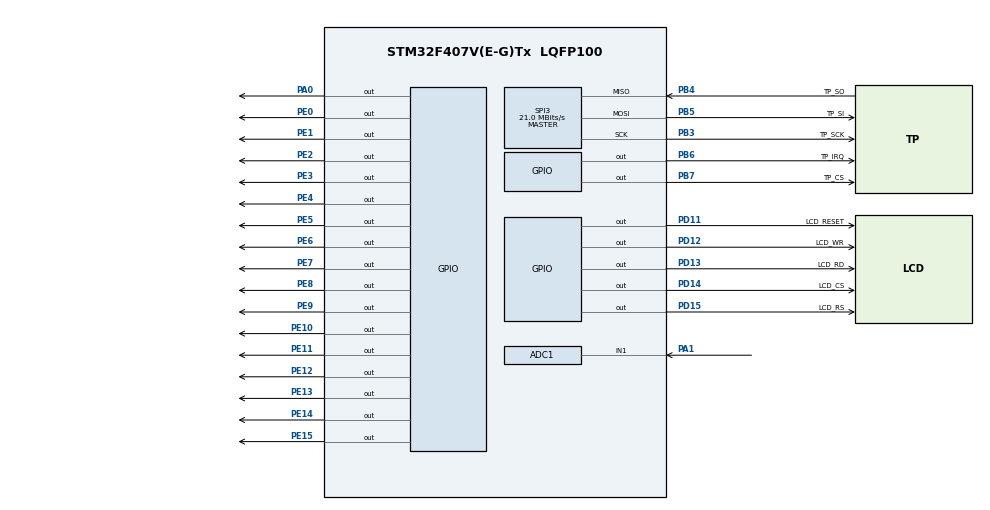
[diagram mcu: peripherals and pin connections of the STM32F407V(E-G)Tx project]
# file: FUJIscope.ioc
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ADC1.Channel-0\#ChannelRegularConversion=ADC_CHANNEL_1
ADC1.ClockPrescaler=ADC_CLOCK_SYNC_PCLK_DIV4
ADC1.ContinuousConvMode=ENABLE
ADC1.DMAContinuousRequests=ENABLE
ADC1.DataAlign=ADC_DATAALIGN_RIGHT
ADC1.DiscontinuousConvMode=DISABLE
ADC1.EOCSelection=ADC_EOC_SINGLE_CONV
ADC1.EnableAnalogWatchDog=false
ADC1.ExternalTrigConv=ADC_SOFTWARE_START
ADC1.ExternalTrigConvEdge=ADC_EXTERNALTRIGCONVEDGE_NONE
ADC1.InjNumberOfConversion=0
ADC1.NbrOfConversion=1
ADC1.NbrOfConversionFlag=1
ADC1.Rank-0\#ChannelRegularConversion=1
ADC1.Resolution=ADC_RESOLUTION_12B
ADC1.SamplingTime-0\#ChannelRegularConversion=ADC_SAMPLETIME_3CYCLES
ADC1.ScanConvMode=ENABLE
ADC1.master=1
Dma.ADC1.0.Direction=DMA_PERIPH_TO_MEMORY
Dma.ADC1.0.FIFOMode=DMA_FIFOMODE_ENABLE
Dma.ADC1.0.FIFOThreshold=DMA_FIFO_THRESHOLD_FULL
Dma.ADC1.0.Instance=DMA2_Stream0
Dma.ADC1.0.MemBurst=DMA_MBURST_SINGLE
Dma.ADC1.0.MemDataAlignment=DMA_MDATAALIGN_HALFWORD
Dma.ADC1.0.MemInc=DMA_MINC_ENABLE
Dma.ADC1.0.Mode=DMA_CIRCULAR
Dma.ADC1.0.PeriphBurst=DMA_PBURST_SINGLE
Dma.ADC1.0.PeriphDataAlignment=DMA_PDATAALIGN_HALFWORD
Dma.ADC1.0.PeriphInc=DMA_PINC_DISABLE
Dma.ADC1.0.Priority=DMA_PRIORITY_LOW
Dma.Request0=ADC1
FREERTOS.Tasks01=defaultTask,0,128,StartDefaultTask,Default,NULL
Mcu.Family=STM32F4
Mcu.Name=STM32F407V(E-G)Tx
Mcu.Package=LQFP100
NVIC.DMA2_Stream0_IRQn=true\:5\:0\:false\:false\:true\:true
NVIC.PriorityGroup=NVIC_PRIORITYGROUP_4
PA0-WKUP.Signal=GPIO_Output
PA1.Signal=ADCx_IN1
PB3.GPIO_Label=TP_SCK
PB3.Mode=Full_Duplex_Master
PB3.Signal=SPI3_SCK
PB4.GPIO_Label=TP_SO
PB4.Mode=Full_Duplex_Master
PB4.Signal=SPI3_MISO
PB5.GPIO_Label=TP_SI
PB5.Mode=Full_Duplex_Master
PB5.Signal=SPI3_MOSI
PB6.GPIO_Label=TP_IRQ
PB6.Signal=GPIO_Output
PB7.GPIO_Label=TP_CS
PB7.Signal=GPIO_Output
PD11.GPIO_Label=LCD_RESET
PD11.Signal=GPIO_Output
PD12.GPIO_Label=LCD_WR
PD12.Signal=GPIO_Output
PD13.GPIO_Label=LCD_RD
PD13.Signal=GPIO_Output
PD14.GPIO_Label=LCD_CS
PD14.Signal=GPIO_Output
PD15.GPIO_Label=LCD_RS
PD15.Signal=GPIO_Output
PE0.Signal=GPIO_Output
PE1.Signal=GPIO_Output
PE10.Signal=GPIO_Output
PE11.Signal=GPIO_Output
PE12.Signal=GPIO_Output
PE13.Signal=GPIO_Output
PE14.Signal=GPIO_Output
PE15.Signal=GPIO_Output
PE2.Signal=GPIO_Output
PE3.Signal=GPIO_Output
PE4.Signal=GPIO_Output
PE5.Signal=GPIO_Output
PE6.Signal=GPIO_Output
PE7.Signal=GPIO_Output
PE8.Signal=GPIO_Output
PE9.Signal=GPIO_Output
PH0-OSC_IN.Mode=HSE-External-Oscillator
PH0-OSC_IN.Signal=RCC_OSC_IN
PH1-OSC_OUT.Mode=HSE-External-Oscillator
PH1-OSC_OUT.Signal=RCC_OSC_OUT
ProjectManager.HeapSize=0x200
ProjectManager.StackSize=0x400
ProjectManager.TargetToolchain=SW4STM32
RCC.48MHZClocksFreq_Value=42000000
RCC.AHBFreq_Value=168000000
RCC.APB1CLKDivider=RCC_HCLK_DIV4
RCC.APB1Freq_Value=42000000
RCC.APB1TimFreq_Value=84000000
RCC.APB2CLKDivider=RCC_HCLK_DIV2
RCC.APB2Freq_Value=84000000
RCC.APB2TimFreq_Value=168000000
RCC.CortexFreq_Value=168000000
RCC.EnbaleCSS=true
RCC.HCLKFreq_Value=168000000
RCC.HSE_VALUE=25000000
RCC.HSI_VALUE=16000000
RCC.LSE_VALUE=32768
RCC.PLLM=25
RCC.PLLN=336
RCC.PLLQ=8
RCC.PLLSourceVirtual=RCC_PLLSOURCE_HSE
RCC.SYSCLKFreq_VALUE=168000000
RCC.SYSCLKSource=RCC_SYSCLKSOURCE_PLLCLK
RCC.VCOOutputFreq_Value=336000000
SH.ADCx_IN1.0=ADC1_IN1,IN1
SPI3.BaudRatePrescaler=SPI_BAUDRATEPRESCALER_2
SPI3.CalculateBaudRate=21.0 MBits/s
SPI3.Direction=SPI_DIRECTION_2LINES
SPI3.Mode=SPI_MODE_MASTER
SPI3.VirtualType=VM_MASTER
VP_FREERTOS_VS_ENABLE.Mode=Enabled
VP_RNG_VS_RNG.Mode=RNG_Activate
board=FUJIscope

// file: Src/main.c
#include <math.h>
#include "main.h"
#include "stm32f4xx_hal.h"
#include "cmsis_os.h"
#include "adc.h"
#include "dma.h"
#include "rng.h"
#include "spi.h"
#include "gpio.h"
#include "LCD.h"
#include "Tpad.h"
#include "ff.h"

#include "gfx.h"
#include "ui.h"

void SystemClock_Config(void);
void Error_Handler(void);
void MX_FREERTOS_Init(void);

#define PI 3.14159265
static uint16_t ADC_buffer[320]={};

osThreadId UI_TaskHandle;
osThreadId ADC_TaskHandle;
__IO uint16_t ADC_val=0;

/*
void LED1_blink_Task(void const * argument)
{
  for(;;)
  {
    HAL_GPIO_TogglePin(GPIOD,GPIO_PIN_12);
    osDelay(500);
  }
}
void LED2_blink_Task(void const * argument)
{
  for(;;)
  {
    HAL_GPIO_TogglePin(GPIOD,GPIO_PIN_13);
    osDelay(1000);
  }
}
*/

void ADC_Task()
{
  MX_ADC1_Init();
  HAL_ADC_Start_DMA(&hadc1, (uint32_t*)&ADC_val,1);
  HAL_ADC_Start(&hadc1);
  while(1)
  {

  }
}

int main(void)
{

  HAL_Init();

  SystemClock_Config();

  MX_GPIO_Init();
  MX_DMA_Init();
  MX_RNG_Init();
  MX_SPI3_Init();
//  LCD_Initializtion();
  MX_ADC1_Init();
  HAL_ADC_Start_DMA(&hadc1, (uint32_t*)&ADC_val,1);
  HAL_ADC_Start(&hadc1);

/*
  osThreadDef(my_ADC_Task, ADC_Task, osPriorityRealtime, 1, 2048);
  ADC_TaskHandle = osThreadCreate(osThread(my_ADC_Task), NULL);
*/
  osThreadDef(UI_Task, UserInterface, osPriorityHigh, 1, 1024);
  UI_TaskHandle = osThreadCreate(osThread(UI_Task), NULL);

  osKernelStart();
}

/** System Clock Configuration
*/
void SystemClock_Config(void)
{

  RCC_OscInitTypeDef RCC_OscInitStruct;
  RCC_ClkInitTypeDef RCC_ClkInitStruct;

    /**Configure the main internal regulator output voltage
    */
  __PWR_CLK_ENABLE();

  __HAL_PWR_VOLTAGESCALING_CONFIG(PWR_REGULATOR_VOLTAGE_SCALE1);

    /**Initializes the CPU, AHB and APB busses clocks
    */
  RCC_OscInitStruct.OscillatorType = RCC_OSCILLATORTYPE_HSE;
  RCC_OscInitStruct.HSEState = RCC_HSE_ON;
  RCC_OscInitStruct.PLL.PLLState = RCC_PLL_ON;
  RCC_OscInitStruct.PLL.PLLSource = RCC_PLLSOURCE_HSE;
  RCC_OscInitStruct.PLL.PLLM = 23;
  RCC_OscInitStruct.PLL.PLLN = 334;
  RCC_OscInitStruct.PLL.PLLP = RCC_PLLP_DIV2;
  RCC_OscInitStruct.PLL.PLLQ = 8;
  HAL_RCC_OscConfig(&RCC_OscInitStruct);

    /**Initializes the CPU, AHB and APB busses clocks
    */
  RCC_ClkInitStruct.ClockType = RCC_CLOCKTYPE_HCLK|RCC_CLOCKTYPE_SYSCLK
                              |RCC_CLOCKTYPE_PCLK1|RCC_CLOCKTYPE_PCLK2;
  RCC_ClkInitStruct.SYSCLKSource = RCC_SYSCLKSOURCE_PLLCLK;
  RCC_ClkInitStruct.AHBCLKDivider = RCC_SYSCLK_DIV1;
  RCC_ClkInitStruct.APB1CLKDivider = RCC_HCLK_DIV4;
  RCC_ClkInitStruct.APB2CLKDivider = RCC_HCLK_DIV2;

  HAL_RCC_ClockConfig(&RCC_ClkInitStruct, FLASH_LATENCY_5);

}

void Error_Handler(void)
{
  while(1)
  {
  }
}

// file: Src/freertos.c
/**
  ******************************************************************************
  * File Name          : freertos.c
  * Description        : Code for freertos applications
  ******************************************************************************
  *
  * Copyright (c) 2017 STMicroelectronics International N.V.
  * All rights reserved.
  *
  * Redistribution and use in source and binary forms, with or without
  * modification, are permitted, provided that the following conditions are met:
  *
  * 1. Redistribution of source code must retain the above copyright notice,
  *    this list of conditions and the following disclaimer.
  * 2. Redistributions in binary form must reproduce the above copyright notice,
  *    this list of conditions and the following disclaimer in the documentation
  *    and/or other materials provided with the distribution.
  * 3. Neither the name of STMicroelectronics nor the names of other
  *    contributors to this software may be used to endorse or promote products
  *    derived from this software without specific written permission.
  * 4. This software, including modifications and/or derivative works of this
  *    software, must execute solely and exclusively on microcontroller or
  *    microprocessor devices manufactured by or for STMicroelectronics.
  * 5. Redistribution and use of this software other than as permitted under
  *    this license is void and will automatically terminate your rights under
  *    this license.
  *
  * THIS SOFTWARE IS PROVIDED BY STMICROELECTRONICS AND CONTRIBUTORS "AS IS"
  * AND ANY EXPRESS, IMPLIED OR STATUTORY WARRANTIES, INCLUDING, BUT NOT
  * LIMITED TO, THE IMPLIED WARRANTIES OF MERCHANTABILITY, FITNESS FOR A
  * PARTICULAR PURPOSE AND NON-INFRINGEMENT OF THIRD PARTY INTELLECTUAL PROPERTY
  * RIGHTS ARE DISCLAIMED TO THE FULLEST EXTENT PERMITTED BY LAW. IN NO EVENT
  * SHALL STMICROELECTRONICS OR CONTRIBUTORS BE LIABLE FOR ANY DIRECT, INDIRECT,
  * INCIDENTAL, SPECIAL, EXEMPLARY, OR CONSEQUENTIAL DAMAGES (INCLUDING, BUT NOT
  * LIMITED TO, PROCUREMENT OF SUBSTITUTE GOODS OR SERVICES; LOSS OF USE, DATA,
  * OR PROFITS; OR BUSINESS INTERRUPTION) HOWEVER CAUSED AND ON ANY THEORY OF
  * LIABILITY, WHETHER IN CONTRACT, STRICT LIABILITY, OR TORT (INCLUDING
  * NEGLIGENCE OR OTHERWISE) ARISING IN ANY WAY OUT OF THE USE OF THIS SOFTWARE,
  * EVEN IF ADVISED OF THE POSSIBILITY OF SUCH DAMAGE.
  *
  ******************************************************************************
  */

#include "FreeRTOS.h"
#include "task.h"
#include "cmsis_os.h"

osThreadId defaultTaskHandle;

void StartDefaultTask(void const * argument);

void MX_FREERTOS_Init(void); /* (MISRA C 2004 rule 8.1) */

/* Hook prototypes */

/* Init FreeRTOS */

void MX_FREERTOS_Init(void) {

  /* Create the thread(s) */
  /* definition and creation of defaultTask */
  osThreadDef(defaultTask, StartDefaultTask, osPriorityNormal, 0, 128);
  defaultTaskHandle = osThreadCreate(osThread(defaultTask), NULL);

}

/* StartDefaultTask function */
void StartDefaultTask(void const * argument)
{

  for(;;)
  {
    osDelay(1);
  }
}

/************************ (C) COPYRIGHT STMicroelectronics *****END OF FILE****/
